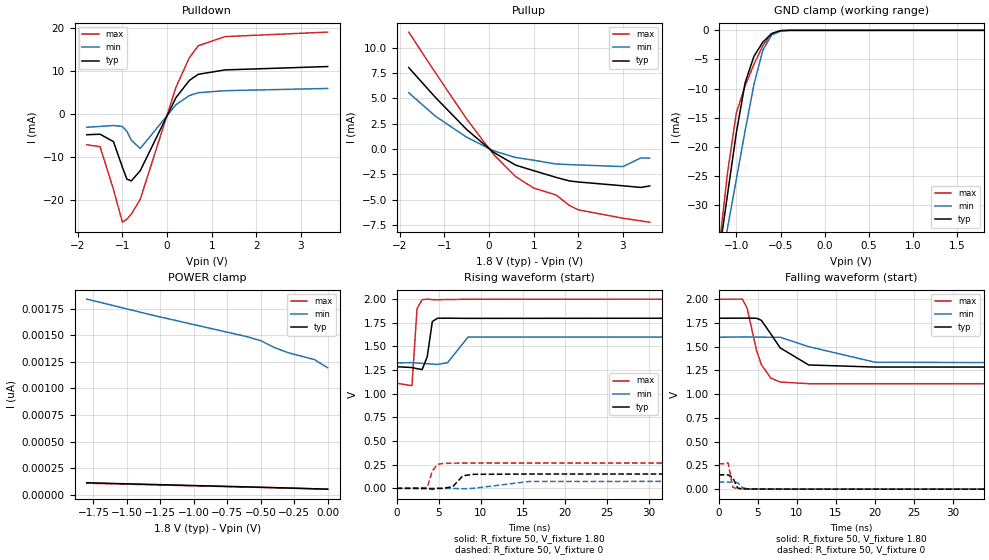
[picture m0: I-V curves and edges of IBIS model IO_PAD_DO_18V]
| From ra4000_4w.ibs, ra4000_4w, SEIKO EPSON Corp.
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[Model]   IO_PAD_DO_18V
Model_type 3-state
Enable Active-High
Polarity Non-Inverting
Vmeas=0.90
C_comp   2.5p   2.0p   3.0p
[Temperature Range] 25   125   -40
[Voltage Range]   1.80   1.60   2.00
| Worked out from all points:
|   slope of the pulldown table from 0 to 0.27 V, typ, clamps not added: 54.4 ohm
|   slope of the pullup table from 0 to 0.27 V, typ, clamps not added: 325 ohm
|   GND clamp passes 1 mA (typ) near -0.63 V on its own axis
|   falling waveform, R_fixture 50, V_fixture 1.80: 20-80 % time 2.9ns typ, 5.03ns min, 1.76ns max; typ from 1.8 V to 1.29 V
|   falling waveform, R_fixture 50, V_fixture 0: 20-80 % time 513ps typ, 617ps min, 380ps max; typ from 0.151 V to 0 V
|   rising waveform, R_fixture 50, V_fixture 1.80: 20-80 % time 511ps typ, 923ps min, 396ps max; typ from 1.29 V to 1.8 V
|   rising waveform, R_fixture 50, V_fixture 0: 20-80 % time 928ps typ, 1.55ns min, 718ps max; typ from 0 V to 0.151 V
[Pullup]
-1.8V     8.019mA    5.543mA    11.52mA
-1.2V     5.073mA    3.223mA    7.502mA
-500mV    1.91mA     1.152mA    2.939mA
100mV     -328.1uA   -184uA     -533.3uA
600mV     -1.606mA   -849uA     -2.738mA
1V        -2.14mA    -1.11mA    -3.857mA
1.5V      -2.802mA   -1.485mA   -4.534mA
1.8V      -3.153mA   -1.545mA   -5.569mA
2V        -3.258mA   -1.577mA   -6.004mA
3V        -3.633mA   -1.74mA    -6.831mA
3.4V      -3.796mA   -893.1uA   -7.094mA
3.6V      -3.649mA   -897.2uA   -7.222mA
[Pulldown]
-1.8V     -4.763mA   -3.037mA   -7.1mA
-1.5V     -4.644mA   -2.829mA   -7.544mA
-1.2V     -6.372mA   -2.614mA   -17.48mA
-1V       -12.3mA    -2.856mA   -25.07mA
-900mV    -15.07mA   -3.983mA   -24.38mA
-800mV    -15.48mA   -6.028mA   -23.19mA
-600mV    -13.11mA   -7.969mA   -19.76mA
200mV     3.863mA    2.205mA    6.265mA
500mV     7.84mA     4.339mA    13.11mA
700mV     9.268mA    4.991mA    15.9mA
1.3V      10.29mA    5.463mA    18.02mA
3.6V      11.07mA    5.981mA    19.07mA
[GND Clamp]
-1.8V     -104.1mA   -95.6mA    -119.3mA
-1.2V     -38.9mA    -42.39mA   -37.89mA
-1.1V     -28.19mA   -33.96mA   -24.51mA
-1V       -17.59mA   -25.56mA   -14.19mA
-900mV    -8.966mA   -17.19mA   -9.504mA
-800mV    -4.444mA   -9.251mA   -5.814mA
-700mV    -2.032mA   -3.411mA   -2.637mA
-600mV    -545.2uA   -802.2uA   -605.7uA
-500mV    -56.87uA   -135.4uA   -35.51uA
-400mV    -3.146uA   -16.86uA   -733.4nA
1.8V      53.94pA    1.303nA    47.64pA
[POWER Clamp]
-1.8V     114.1pA    1.839nA    110pA
-1.3V     97.76pA    1.685nA    94.59pA
-600mV    75.14pA    1.485nA    73.08pA
-500mV    71.92pA    1.448nA    70.04pA
-400mV    68.56pA    1.385nA    66.99pA
-300mV    64.96pA    1.337nA    63.73pA
-100mV    57.73pA    1.271nA    57.18pA
0V        53.94pA    1.194nA    54.02pA
[Falling Waveform]
R_fixture=50
V_fixture=1.80
V_fixture_min=1.60
V_fixture_max=2.00
0s        1.8V       1.6V       2V
3.03ns    1.801V     1.603V     2.002V
3.636ns   1.801V     1.603V     1.909V
4.848ns   1.8V       1.601V     1.461V
5.455ns   1.779V     1.601V     1.314V
6.667ns   1.636V     1.6V       1.17V
7.879ns   1.488V     1.6V       1.128V
11.52ns   1.308V     1.501V     1.111V
20ns      1.286V     1.337V     1.111V
60ns      1.286V     1.326V     1.111V
[Falling Waveform]
R_fixture=50
V_fixture=0
V_fixture_min=0
V_fixture_max=0
0s        151.3mV    74.58mV    268mV
606.1ps   151.3mV    74.6mV     268mV
1.212ns   150.2mV    74.11mV    276.3mV
1.818ns   120.7mV    75.52mV    19.66mV
2.424ns   12.64mV    67.67mV    4.205mV
3.03ns    2.15mV     17.3mV     4.18mV
3.636ns   2.078mV    3.791mV    2.977mV
4.242ns   1.854mV    995uV      1.631mV
12.12ns   86.45uV    497.8uV    30.95uV
60ns      3.525uV    5.42uV     2.028uV
[Rising Waveform]
R_fixture=50
V_fixture=1.80
V_fixture_min=1.60
V_fixture_max=2.00
0s        1.286V     1.326V     1.111V
1.818ns   1.277V     1.329V     1.085V
2.424ns   1.265V     1.325V     1.9V
3.03ns    1.256V     1.321V     1.994V
3.636ns   1.391V     1.317V     2.001V
4.242ns   1.763V     1.314V     1.995V
4.848ns   1.798V     1.31V      1.994V
6.061ns   1.799V     1.329V     1.996V
8.485ns   1.797V     1.599V     1.999V
60ns      1.8V       1.6V       2V
[Rising Waveform]
R_fixture=50
V_fixture=0
V_fixture_min=0
V_fixture_max=0
0s        358.6pV    2.359nV    283.7pV
3.636ns   -2.144mV   54.51uV    8.597mV
4.242ns   -8.784mV   45.48uV    182.6mV
4.848ns   -355.5uV   38.28uV    254.3mV
5.455ns   -855uV     -29.41uV   262.6mV
6.667ns   17.43mV    -1.41mV    266.6mV
7.879ns   132.9mV    -4.124mV   267.6mV
9.091ns   148.1mV    -287.1uV   267.8mV
15.76ns   151.2mV    72.6mV     267.9mV
60ns      151.3mV    74.58mV    268mV
[Ramp]
R_load=50
dV/dt_r   9.075E-2/8.497E-10   4.475E-2/1.531E-9   1.608E-1/4.731E-10
dV/dt_f   3.085E-1/2.890E-9   1.642E-1/5.008E-9   5.334E-1/1.719E-9
|[End   IO_PAD_DO_18V
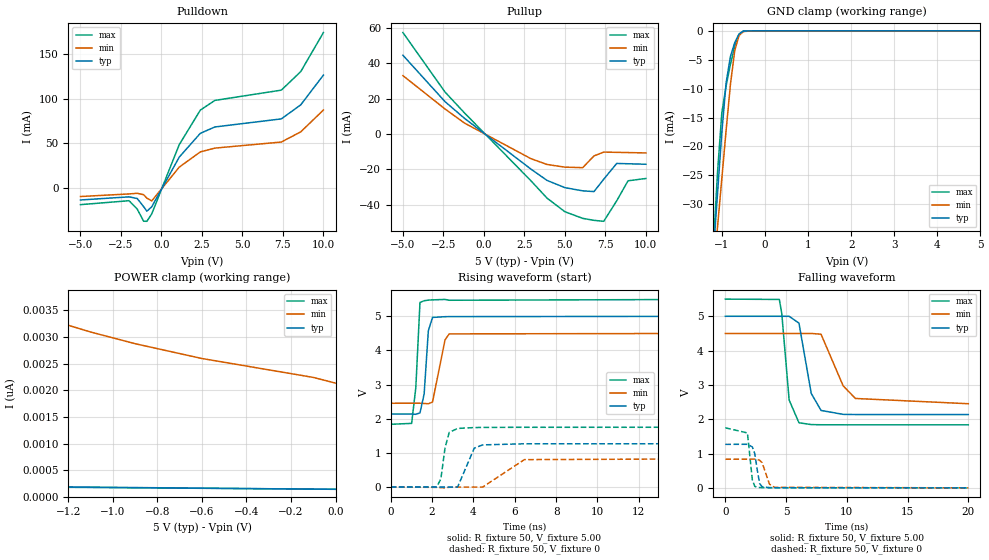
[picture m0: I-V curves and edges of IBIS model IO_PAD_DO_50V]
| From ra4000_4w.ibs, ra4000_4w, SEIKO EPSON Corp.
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[Model]   IO_PAD_DO_50V
Model_type 3-state
Enable Active-High
Polarity Non-Inverting
Vmeas=2.50
C_comp   2.5p   2.0p   3.0p
[Temperature Range] 25   125   -40
[Voltage Range]   5.00   4.50   5.50
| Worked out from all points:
|   slope of the pulldown table from 0 to 0.75 V, typ, clamps not added: 30.2 ohm
|   slope of the pullup table from 0 to 0.75 V, typ, clamps not added: 143 ohm
|   GND clamp passes 1 mA (typ) near -0.63 V on its own axis
|   falling waveform, R_fixture 50, V_fixture 5.00: 20-80 % time 860ps typ, 1.46ns min, 533ps max; typ from 5 V to 2.14 V
|   falling waveform, R_fixture 50, V_fixture 0: 20-80 % time 356ps typ, 467ps min, 302ps max; typ from 1.27 V to 0 V
|   rising waveform, R_fixture 50, V_fixture 5.00: 20-80 % time 193ps typ, 327ps min, 216ps max; typ from 2.14 V to 5 V
|   rising waveform, R_fixture 50, V_fixture 0: 20-80 % time 406ps typ, 610ps min, 290ps max; typ from 0 V to 1.27 V
[Pullup]
-5V       44.6mA     33.06mA    57.43mA
-2.4V     18.33mA    14.17mA    23.76mA
-1.2V     8.881mA    6.2mA      11.95mA
2.9V      -19.85mA   -13.95mA   -26.45mA
3.9V      -26.28mA   -17.26mA   -36.32mA
5V        -30.37mA   -18.76mA   -44mA
6.1V      -32.18mA   -19.06mA   -47.77mA
6.8V      -32.6mA    -12.39mA   -48.89mA
7.4V      -25.59mA   -10.25mA   -49.43mA
8.2V      -16.68mA   -10.39mA   -37.84mA
8.9V      -16.85mA   -10.51mA   -26.5mA
10V       -17.13mA   -10.72mA   -25.19mA
[Pulldown]
-5V       -13.17mA   -9.306mA   -18.37mA
-2V       -9.661mA   -6.412mA   -13.97mA
-1.5V     -11.48mA   -5.698mA   -23.2mA
-1.1V     -20.65mA   -7.262mA   -36.89mA
-900mV    -25.65mA   -11.11mA   -36.97mA
-600mV    -20.79mA   -14.18mA   -28.65mA
1.1V      34.77mA    23.54mA    48.65mA
2.4V      61.28mA    40.54mA    87.21mA
3.3V      68.39mA    44.77mA    98.05mA
7.4V      77.39mA    51.54mA    109.5mA
8.6V      93.1mA     62.91mA    130.2mA
10V       126.3mA    87.31mA    173.8mA
[GND Clamp]
-5V       -506.4mA   -412.3mA   -621.4mA
-1.2V     -38.91mA   -42.39mA   -37.89mA
-1.1V     -28.19mA   -33.97mA   -24.51mA
-1V       -17.59mA   -25.57mA   -14.19mA
-900mV    -8.974mA   -17.2mA    -9.505mA
-800mV    -4.446mA   -9.258mA   -5.814mA
-700mV    -2.032mA   -3.417mA   -2.637mA
-600mV    -545.2uA   -803.1uA   -605.7uA
-500mV    -56.87uA   -135.4uA   -35.51uA
-300mV    -121.9nA   -1.689uA   -9.382nA
5V        146.4pA    2.515nA    131.9pA
[POWER Clamp]
-5V       431.4pA    19.14nA    8.229uA
-4.7V     402.6pA    16.7nA     4.225nA
-4.6V     393.7pA    15.95nA    333.2pA
-4.5V     385pA      15.23nA    288pA
-1.7V     212.5pA    3.956nA    199.3pA
-1.6V     208.1pA    3.788nA    196.3pA
-1.3V     195.4pA    3.342nA    187pA
-1.1V     187.2pA    3.091nA    180.8pA
-900mV    179.4pA    2.872nA    174.6pA
-600mV    168pA      2.595nA    165.4pA
-100mV    150pA      2.241nA    150.7pA
0V        146.4pA    2.134nA    148pA
[Falling Waveform]
R_fixture=50
V_fixture=5.00
V_fixture_min=4.50
V_fixture_max=5.50
0s        5V         4.5V       5.5V
4.444ns   5V         4.5V       5.491V
4.646ns   5V         4.5V       5.079V
5.253ns   5V         4.5V       2.56V
6.061ns   4.8V       4.5V       1.897V
7.071ns   2.752V     4.5V       1.844V
7.879ns   2.256V     4.478V     1.839V
9.697ns   2.142V     2.973V     1.838V
10.71ns   2.137V     2.605V     1.837V
20ns      2.136V     2.452V     1.837V
[Falling Waveform]
R_fixture=50
V_fixture=0
V_fixture_min=0
V_fixture_max=0
0s        1.268V     834.1mV    1.75V
1.818ns   1.27V      834.8mV    1.6V
2.222ns   1.193V     838.2mV    232.3mV
2.424ns   995.9mV    838mV      43.08mV
2.626ns   521.5mV    829.7mV    15.72mV
2.828ns   121.5mV    801.7mV    9.397mV
3.03ns    32.22mV    732.4mV    7.198mV
3.636ns   5.382mV    105mV      4.711mV
4.04ns    3.64mV     15.55mV    3.983mV
20ns      19.55uV    24.51uV    2.878uV
[Rising Waveform]
R_fixture=50
V_fixture=5.00
V_fixture_min=4.50
V_fixture_max=5.50
0s        2.136V     2.452V     1.837V
1.01ns    2.136V     2.454V     1.863V
1.212ns   2.129V     2.454V     2.906V
1.414ns   2.171V     2.453V     5.403V
1.616ns   2.727V     2.446V     5.453V
1.818ns   4.574V     2.438V     5.471V
2.02ns    4.964V     2.486V     5.478V
2.626ns   4.986V     4.307V     5.491V
2.828ns   4.988V     4.483V     5.467V
20ns      5V         4.5V       5.5V
[Rising Waveform]
R_fixture=50
V_fixture=0
V_fixture_min=0
V_fixture_max=0
0s        747.6pV    2.593nV    641.8pV
2.222ns   -482.4uV   -8.866mV   1.254uV
2.424ns   -80.33uV   -17.76mV   238.9mV
2.626ns   44.27uV    -23.83mV   1.148V
2.828ns   -276.3uV   -6.782mV   1.599V
3.232ns   -1.876mV   -212.8uV   1.715V
4.04ns    1.138V     57.98uV    1.741V
4.444ns   1.234V     -991.8uV   1.745V
6.465ns   1.266V     802.7mV    1.749V
20ns      1.268V     834.1mV    1.75V
[Ramp]
R_load=50
dV/dt_r   7.608E-1/3.628E-10   5.004E-1/6.054E-10   1.050E+0/2.426E-10
dV/dt_f   1.719E+0/8.519E-10   1.229E+0/1.454E-9   2.198E+0/5.284E-10
|[End   IO_PAD_DO_50V
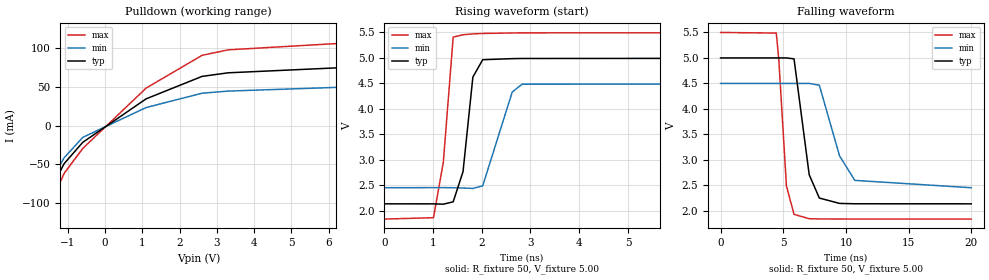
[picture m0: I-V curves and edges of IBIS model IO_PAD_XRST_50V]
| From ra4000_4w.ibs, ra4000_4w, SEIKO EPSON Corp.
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[Model]   IO_PAD_XRST_50V
Model_type Open_drain
Polarity Non-Inverting
Vref=5.50
Vmeas=2.50
Rref=5000
C_comp   2.5p   2.0p   3.0p
[Temperature Range] 25   125   -40
[Voltage Range]   5.00   4.50   5.50
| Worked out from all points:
|   slope of the pulldown table from 0 to 0.75 V, typ, clamps not added: 30.2 ohm
|   falling waveform, R_fixture 50, V_fixture 5.00: 20-80 % time 854ps typ, 1.48ns min, 538ps max; typ from 5 V to 2.14 V
|   rising waveform, R_fixture 50, V_fixture 5.00: 20-80 % time 201ps typ, 325ps min, 220ps max; typ from 2.14 V to 5 V
[Pulldown]
-5V       -476.2mA   -385.2mA   -587.9mA
-2.3V     -168.7mA   -143mA     -202.3mA
-2V       -135.4mA   -116.8mA   -160.7mA
-1.8V     -113.3mA   -99.43mA   -136.1mA
-1.1V     -48.86mA   -41.26mA   -61.43mA
-600mV    -21.34mA   -14.99mA   -29.25mA
1.1V      34.77mA    23.54mA    48.65mA
2.6V      63.75mA    42.01mA    90.93mA
3.3V      68.39mA    44.77mA    98.05mA
7.4V      77.39mA    51.54mA    109.5mA
8.8V      96.9mA     65.68mA    135.2mA
10V       126.3mA    87.31mA    173.8mA
[Falling Waveform]
R_fixture=50
V_fixture=5.00
V_fixture_min=4.50
V_fixture_max=5.50
0s        5V         4.5V       5.5V
4.444ns   5V         4.5V       5.488V
4.646ns   5V         4.5V       4.96V
5.253ns   5V         4.5V       2.486V
5.859ns   4.982V     4.5V       1.929V
7.071ns   2.706V     4.5V       1.844V
7.879ns   2.249V     4.463V     1.839V
9.495ns   2.144V     3.076V     1.838V
10.71ns   2.137V     2.596V     1.837V
20ns      2.136V     2.452V     1.837V
[Rising Waveform]
R_fixture=50
V_fixture=5.00
V_fixture_min=4.50
V_fixture_max=5.50
0s        2.136V     2.452V     1.837V
1.01ns    2.135V     2.454V     1.863V
1.212ns   2.129V     2.454V     2.954V
1.414ns   2.175V     2.452V     5.408V
1.616ns   2.768V     2.446V     5.455V
1.818ns   4.624V     2.438V     5.472V
2.02ns    4.965V     2.49V      5.48V
2.626ns   4.986V     4.332V     5.49V
2.828ns   4.989V     4.484V     5.492V
20ns      5V         4.5V       5.5V
[Ramp]
R_load=50
dV/dt_r   1.719E+0/1.791E-10   1.229E+0/3.065E-10   2.198E+0/1.305E-10
dV/dt_f   1.719E+0/8.483E-10   1.229E+0/1.465E-9   2.198E+0/5.262E-10
|[End   IO_PAD_XRST_50V
